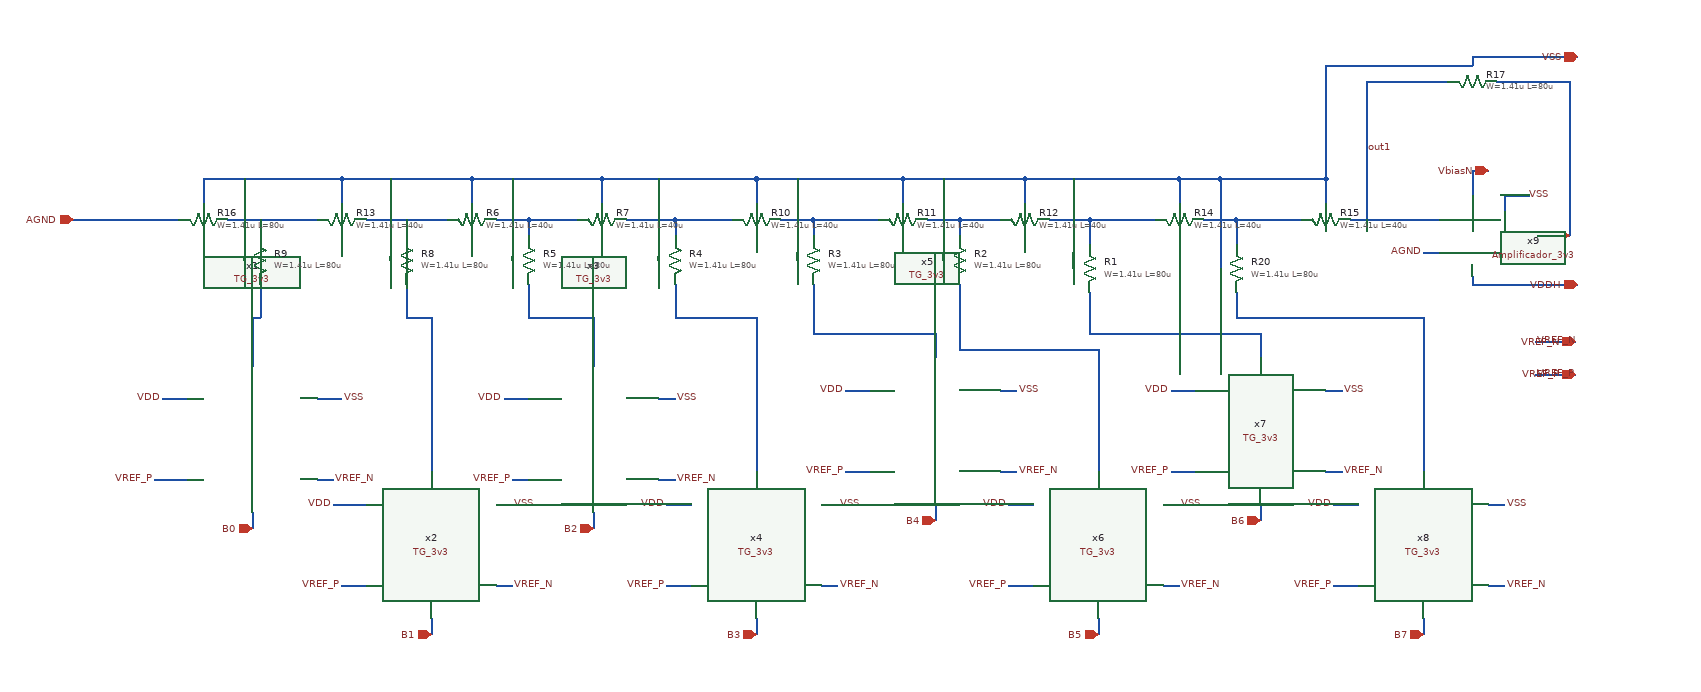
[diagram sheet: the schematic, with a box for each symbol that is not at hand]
v {xschem version=3.4.8RC file_version=1.3}
G {}
K {}
V {}
S {}
F {}
E {}
N 370 -160 480 -160 {
lab=#net1}
N 410 -160 410 -140 {
lab=#net1}
N 540 -160 640 -160 {
lab=#net2}
N 590 -160 590 -140 {
lab=#net2}
N 700 -160 740 -160 {
lab=#net3}
N 740 -160 740 -140 {
lab=#net3}
N 740 -160 800 -160 {
lab=#net3}
N 860 -160 920 -160 {
lab=#net4}
N 920 -160 920 -140 {
lab=#net4}
N 920 -160 990 -160 {
lab=#net4}
N 1050 -160 1090 -160 {
lab=#net5}
N 1090 -160 1090 -140 {
lab=#net5}
N 1090 -160 1170 -160 {
lab=#net5}
N 1230 -160 1270 -160 {
lab=#net6}
N 1270 -160 1270 -140 {
lab=#net6}
N 1270 -160 1320 -160 {
lab=#net6}
N 1380 -160 1430 -160 {
lab=#net7}
N 1430 -160 1430 -130 {
lab=#net7}
N 1430 -160 1510 -160 {
lab=#net7}
N 1570 -160 1610 -160 {
lab=#net8}
N 1610 -160 1610 -130 {
lab=#net8}
N 1610 -160 1690 -160 {
lab=#net8}
N 1750 -160 1860 -160 {
lab=out1}
N 1770 -330 1770 -160 {
lab=out1}
N 1770 -330 1810 -330 {
lab=out1}
N 1810 -330 1870 -330 {
lab=out1}
N 340 -210 340 -180 {
lab=VSS}
N 340 -210 510 -210 {
lab=VSS}
N 390 -210 390 -110 {
lab=VSS}
N 510 -210 510 -180 {
lab=VSS}
N 510 -210 670 -210 {
lab=VSS}
N 570 -210 570 -110 {
lab=VSS}
N 670 -210 670 -180 {
lab=VSS}
N 670 -210 830 -210 {
lab=VSS}
N 720 -210 720 -110 {
lab=VSS}
N 830 -210 830 -180 {
lab=VSS}
N 830 -210 1020 -210 {
lab=VSS}
N 900 -210 900 -110 {
lab=VSS}
N 1020 -210 1020 -180 {
lab=VSS}
N 1020 -210 1200 -210 {
lab=VSS}
N 1070 -210 1070 -110 {
lab=VSS}
N 1200 -210 1200 -180 {
lab=VSS}
N 1200 -210 1350 -210 {
lab=VSS}
N 1250 -210 1250 -110 {
lab=VSS}
N 1350 -210 1350 -180 {
lab=VSS}
N 1350 -210 1540 -210 {
lab=VSS}
N 1410 -210 1410 -100 {
lab=VSS}
N 1540 -210 1540 -180 {
lab=VSS}
N 1540 -210 1590 -210 {
lab=VSS}
N 1590 -210 1590 -100 {
lab=VSS}
N 1590 -210 1720 -210 {
lab=VSS}
N 1720 -210 1720 -180 {
lab=VSS}
N 1720 -350 1720 -210 {
lab=VSS}
N 1720 -350 1730 -350 {
lab=VSS}
N 1730 -350 1900 -350 {
lab=VSS}
N 1900 -360 1900 -350 {
lab=VSS}
N 1900 -360 2030 -360 {
lab=VSS}
N 1930 -330 1950 -330 {
lab=OUT}
N 1950 -330 2020 -330 {
lab=OUT}
N 2020 -330 2020 -150 {
lab=OUT}
N 2020 -150 2020 -140 {
lab=OUT}
N 1840 -120 1860 -120 {
lab=AGND}
N 1900 -90 1900 -80 {
lab=VDDH}
N 1900 -80 1940 -80 {
lab=VDDH}
N 1940 -80 2030 -80 {
lab=VDDH}
N 1900 -220 1920 -220 {
lab=VbiasN}
N 1900 -220 1900 -190 {
lab=VbiasN}
N 1977.5 30 2027.5 30 {
lab=VREF_P}
N 1977.5 -10 2027.5 -10 {
lab=VREF_N}
N 1920 190 1940 190 {
lab=VSS}
N 1920 290 1940 290 {
lab=VREF_N}
N 1730 290 1760 290 {
lab=VREF_P}
N 1730 190 1760 190 {
lab=VDD}
N 1840 330 1840 350 {
lab=B7}
N 1610 -70 1610 -40 {
lab=#net9}
N 1610 -40 1840 -40 {
lab=#net9}
N 1840 -40 1840 150 {
lab=#net9}
N 1720 50 1740 50 {
lab=VSS}
N 1720 150 1740 150 {
lab=VREF_N}
N 1530 150 1560 150 {
lab=VREF_P}
N 1530 50 1560 50 {
lab=VDD}
N 1640 190 1640 210 {
lab=B6}
N 1430 -70 1430 -20 {
lab=#net10}
N 1430 -20 1640 -20 {
lab=#net10}
N 1640 -20 1640 10 {
lab=#net10}
N 1520 190 1540 190 {
lab=VSS}
N 1520 290 1540 290 {
lab=VREF_N}
N 1330 290 1360 290 {
lab=VREF_P}
N 1330 190 1360 190 {
lab=VDD}
N 1440 330 1440 350 {
lab=B5}
N 1270 -80 1270 0 {
lab=#net11}
N 1270 0 1440 0 {
lab=#net11}
N 1440 0 1440 150 {
lab=#net11}
N 1320 50 1340 50 {
lab=VSS}
N 1320 150 1340 150 {
lab=VREF_N}
N 1130 150 1160 150 {
lab=VREF_P}
N 1130 50 1160 50 {
lab=VDD}
N 1240 190 1240 210 {
lab=B4}
N 1090 -80 1090 -20 {
lab=#net12}
N 1090 -20 1240 -20 {
lab=#net12}
N 1240 -20 1240 10 {
lab=#net12}
N 1100 190 1120 190 {
lab=VSS}
N 1100 290 1120 290 {
lab=VREF_N}
N 910 290 940 290 {
lab=VREF_P}
N 910 190 940 190 {
lab=VDD}
N 1020 330 1020 350 {
lab=B3}
N 920 -80 920 -40 {
lab=#net13}
N 920 -40 1020 -40 {
lab=#net13}
N 1020 -40 1020 150 {
lab=#net13}
N 900 60 920 60 {
lab=VSS}
N 900 160 920 160 {
lab=VREF_N}
N 720 160 740 160 {
lab=VREF_P}
N 710 60 740 60 {
lab=VDD}
N 820 200 820 220 {
lab=B2}
N 740 -80 740 -40 {
lab=#net14}
N 740 -40 820 -40 {
lab=#net14}
N 820 -40 820 20 {
lab=#net14}
N 700 190 720 190 {
lab=VSS}
N 700 290 720 290 {
lab=VREF_N}
N 510 290 540 290 {
lab=VREF_P}
N 500 190 540 190 {
lab=VDD}
N 620 330 620 350 {
lab=B1}
N 590 -80 590 -40 {
lab=#net15}
N 590 -40 620 -40 {
lab=#net15}
N 620 -40 620 150 {
lab=#net15}
N 480 60 510 60 {
lab=VSS}
N 480 160 500 160 {
lab=VREF_N}
N 280 160 320 160 {
lab=VREF_P}
N 290 60 320 60 {
lab=VDD}
N 400 200 400 220 {
lab=B0}
N 410 -80 410 -40 {
lab=#net16}
N 400 -40 410 -40 {
lab=#net16}
N 400 -40 400 20 {
lab=#net16}
N 1940 -190 1940 -170 {lab=VSS}
N 1940 -190 1970 -190 {lab=VSS}
N 1980 -140 2020 -140 {lab=OUT}
N 180 -160 310 -160 {lab=AGND}
C {devices/iopin.sym} 180 -160 2 0 {name=p1 lab=AGND}
C {devices/iopin.sym} 2020 -140 0 0 {name=p3 lab=OUT}
C {devices/iopin.sym} 2027.5 30 0 0 {name=p35 lab=VREF_P}
C {devices/iopin.sym} 2027.5 -10 0 0 {name=p36 lab=VREF_N}
C {devices/iopin.sym} 2030 -360 0 0 {name=p67 lab=VSS}
C {devices/iopin.sym} 2030 -80 0 0 {name=p14 lab=VDDH}
C {devices/iopin.sym} 1920 -220 0 0 {name=p42 lab=VbiasN}
C {devices/iopin.sym} 1840 350 1 0 {name=p44 lab=B7}
C {devices/iopin.sym} 1640 210 1 0 {name=p55 lab=B6}
C {devices/iopin.sym} 1440 350 1 0 {name=p71 lab=B5}
C {devices/iopin.sym} 1240 210 1 0 {name=p81 lab=B4}
C {devices/iopin.sym} 1020 350 1 0 {name=p86 lab=B3}
C {devices/iopin.sym} 820 220 1 0 {name=p91 lab=B2}
C {devices/iopin.sym} 620 350 1 0 {name=p96 lab=B1}
C {devices/iopin.sym} 400 220 1 0 {name=p101 lab=B0}
C {devices/lab_wire.sym} 1840 -120 0 0 {name=p2 sig_type=std_logic lab=AGND}
C {devices/lab_wire.sym} 1977.5 30 2 0 {name=p37 sig_type=std_logic lab=VREF_P}
C {devices/lab_wire.sym} 1977.5 -10 2 0 {name=p38 sig_type=std_logic lab=VREF_N}
C {devices/lab_wire.sym} 1967.5 -190 2 0 {name=p4 sig_type=std_logic lab=VSS}
C {devices/lab_pin.sym} 1770 -247.5 0 1 {name=p45 sig_type=std_logic lab=out1}
C {devices/lab_pin.sym} 1940 190 2 0 {name=p39 sig_type=std_logic lab=VSS}
C {devices/lab_pin.sym} 1940 290 2 0 {name=p40 sig_type=std_logic lab=VREF_N}
C {devices/lab_pin.sym} 1730 290 0 0 {name=p41 sig_type=std_logic lab=VREF_P}
C {devices/lab_pin.sym} 1730 190 0 0 {name=p43 sig_type=std_logic lab=VDD}
C {devices/lab_pin.sym} 1740 50 2 0 {name=p48 sig_type=std_logic lab=VSS}
C {devices/lab_pin.sym} 1740 150 2 0 {name=p49 sig_type=std_logic lab=VREF_N}
C {devices/lab_pin.sym} 1530 150 0 0 {name=p50 sig_type=std_logic lab=VREF_P}
C {devices/lab_pin.sym} 1530 50 0 0 {name=p54 sig_type=std_logic lab=VDD}
C {devices/lab_pin.sym} 1540 190 2 0 {name=p56 sig_type=std_logic lab=VSS}
C {devices/lab_pin.sym} 1540 290 2 0 {name=p68 sig_type=std_logic lab=VREF_N}
C {devices/lab_pin.sym} 1330 290 0 0 {name=p69 sig_type=std_logic lab=VREF_P}
C {devices/lab_pin.sym} 1330 190 0 0 {name=p70 sig_type=std_logic lab=VDD}
C {devices/lab_pin.sym} 1340 50 2 0 {name=p73 sig_type=std_logic lab=VSS}
C {devices/lab_pin.sym} 1340 150 2 0 {name=p74 sig_type=std_logic lab=VREF_N}
C {devices/lab_pin.sym} 1130 150 0 0 {name=p79 sig_type=std_logic lab=VREF_P}
C {devices/lab_pin.sym} 1130 50 0 0 {name=p80 sig_type=std_logic lab=VDD}
C {devices/lab_pin.sym} 1120 190 2 0 {name=p82 sig_type=std_logic lab=VSS}
C {devices/lab_pin.sym} 1120 290 2 0 {name=p83 sig_type=std_logic lab=VREF_N}
C {devices/lab_pin.sym} 910 290 0 0 {name=p84 sig_type=std_logic lab=VREF_P}
C {devices/lab_pin.sym} 910 190 0 0 {name=p85 sig_type=std_logic lab=VDD}
C {devices/lab_pin.sym} 920 60 2 0 {name=p87 sig_type=std_logic lab=VSS}
C {devices/lab_pin.sym} 920 160 2 0 {name=p88 sig_type=std_logic lab=VREF_N}
C {devices/lab_pin.sym} 720 160 0 0 {name=p89 sig_type=std_logic lab=VREF_P}
C {devices/lab_pin.sym} 710 60 0 0 {name=p90 sig_type=std_logic lab=VDD}
C {devices/lab_pin.sym} 720 190 2 0 {name=p92 sig_type=std_logic lab=VSS}
C {devices/lab_pin.sym} 720 290 2 0 {name=p93 sig_type=std_logic lab=VREF_N}
C {devices/lab_pin.sym} 510 290 0 0 {name=p94 sig_type=std_logic lab=VREF_P}
C {devices/lab_pin.sym} 500 190 0 0 {name=p95 sig_type=std_logic lab=VDD}
C {devices/lab_pin.sym} 510 60 2 0 {name=p97 sig_type=std_logic lab=VSS}
C {devices/lab_pin.sym} 500 160 2 0 {name=p98 sig_type=std_logic lab=VREF_N}
C {devices/lab_pin.sym} 280 160 0 0 {name=p99 sig_type=std_logic lab=VREF_P}
C {devices/lab_pin.sym} 290 60 0 0 {name=p100 sig_type=std_logic lab=VDD}
C {symbols/ppolyf_u.sym} 1610 -100 0 0 {name=R20
W=1.41u
L=80u
model=ppolyf_u
spiceprefix=X
m=1}
C {DAC/TG_3v3.sym} 380 200 0 0 {name=x1}
C {DAC/TG_3v3.sym} 600 330 0 0 {name=x2}
C {DAC/TG_3v3.sym} 800 200 0 0 {name=x3}
C {DAC/TG_3v3.sym} 1000 330 0 0 {name=x4}
C {DAC/TG_3v3.sym} 1220 190 0 0 {name=x5}
C {DAC/TG_3v3.sym} 1420 330 0 0 {name=x6}
C {DAC/TG_3v3.sym} 1620 190 0 0 {name=x7}
C {DAC/TG_3v3.sym} 1820 330 0 0 {name=x8}
C {AMPLIFICADOR/Amplificador_3v3.sym} 1920 -260 2 1 {name=x9}
C {symbols/ppolyf_u.sym} 510 -160 1 0 {name=R13
W=1.41u
L=40u
model=ppolyf_u
spiceprefix=X
m=1}
C {symbols/ppolyf_u.sym} 670 -160 1 0 {name=R6
W=1.41u
L=40u
model=ppolyf_u
spiceprefix=X
m=1}
C {symbols/ppolyf_u.sym} 830 -160 1 0 {name=R7
W=1.41u
L=40u
model=ppolyf_u
spiceprefix=X
m=1}
C {symbols/ppolyf_u.sym} 1020 -160 1 0 {name=R10
W=1.41u
L=40u
model=ppolyf_u
spiceprefix=X
m=1}
C {symbols/ppolyf_u.sym} 1200 -160 1 0 {name=R11
W=1.41u
L=40u
model=ppolyf_u
spiceprefix=X
m=1}
C {symbols/ppolyf_u.sym} 1350 -160 1 0 {name=R12
W=1.41u
L=40u
model=ppolyf_u
spiceprefix=X
m=1}
C {symbols/ppolyf_u.sym} 1540 -160 1 0 {name=R14
W=1.41u
L=40u
model=ppolyf_u
spiceprefix=X
m=1}
C {symbols/ppolyf_u.sym} 1720 -160 1 0 {name=R15
W=1.41u
L=40u
model=ppolyf_u
spiceprefix=X
m=1}
C {symbols/ppolyf_u.sym} 1430 -100 0 0 {name=R1
W=1.41u
L=80u
model=ppolyf_u
spiceprefix=X
m=1}
C {symbols/ppolyf_u.sym} 1270 -110 0 0 {name=R2
W=1.41u
L=80u
model=ppolyf_u
spiceprefix=X
m=1}
C {symbols/ppolyf_u.sym} 1090 -110 0 0 {name=R3
W=1.41u
L=80u
model=ppolyf_u
spiceprefix=X
m=1}
C {symbols/ppolyf_u.sym} 920 -110 0 0 {name=R4
W=1.41u
L=80u
model=ppolyf_u
spiceprefix=X
m=1}
C {symbols/ppolyf_u.sym} 740 -110 0 0 {name=R5
W=1.41u
L=80u
model=ppolyf_u
spiceprefix=X
m=1}
C {symbols/ppolyf_u.sym} 590 -110 0 0 {name=R8
W=1.41u
L=80u
model=ppolyf_u
spiceprefix=X
m=1}
C {symbols/ppolyf_u.sym} 410 -110 0 0 {name=R9
W=1.41u
L=80u
model=ppolyf_u
spiceprefix=X
m=1}
C {symbols/ppolyf_u.sym} 340 -160 1 0 {name=R16
W=1.41u
L=80u
model=ppolyf_u
spiceprefix=X
m=1}
C {symbols/ppolyf_u.sym} 1900 -330 1 0 {name=R17
W=1.41u
L=80u
model=ppolyf_u
spiceprefix=X
m=1}
